# LEF file generated by Abstract Generator version 5.5.10 on Jul 30 14:47:58 2004
#
# Contains LEF for all bins.
# Options:   [x] Antenna
#            [x] Geometry
#            [x] Technology
VERSION 5.4 ;
NAMESCASESENSITIVE ON ;
BUSBITCHARS "[]" ;
DIVIDERCHAR "/" ;
UNITS
  DATABASE MICRONS 1000 ;
END UNITS

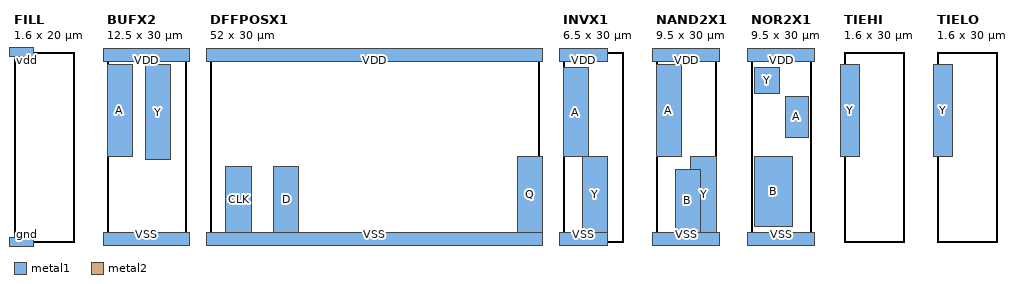
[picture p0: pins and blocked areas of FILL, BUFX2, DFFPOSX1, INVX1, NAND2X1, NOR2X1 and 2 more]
MACRO FILL
  CLASS  CORE ;
  FOREIGN FILL 0.000 0.000 ;
  ORIGIN 0.000 0.000 ;
  SIZE 1.600 BY 20.000 ;
  SYMMETRY X Y ;
  SITE core ;
  PIN gnd    DIRECTION INOUT ;
    USE GROUND ;
    SHAPE ABUTMENT ;
    PORT
      LAYER metal1 ;
        RECT -0.5 -0.5 2 0.5 ;
    END
  END gnd
  PIN vdd    DIRECTION INOUT ;
    USE POWER ;
    SHAPE ABUTMENT ;
    PORT
      LAYER metal1 ;
        RECT -0.5 19.5 2 20.5 ;
    END
  END vdd
END FILL

MACRO BUFX2
  CLASS CORE ;
  SOURCE USER ;
  ORIGIN 0 0 ;
  SIZE 12.500 BY 30.000 ;
  SYMMETRY X Y ;
  SITE unit ;
  
  PIN A    DIRECTION INPUT ;
    USE SIGNAL ;
    PORT
      LAYER metal2 ;
        RECT 0 13.5 4 28 ;
    END
    PORT
      LAYER metal1 ;
        RECT 0 13.5 4 28 ;
    END
  END A
  PIN VDD    DIRECTION INOUT ;
    USE POWER ;
    PORT
      LAYER metal1 ;
        RECT -0.5 28.5 13 30.5 ;
    END
  END VDD
  PIN VSS    DIRECTION INOUT ;
    USE GROUND ;
    PORT
      LAYER metal1 ;
        RECT -0.5 -0.5 13 1.5 ;
    END
  END VSS
  PIN Y    DIRECTION OUTPUT ;
    USE SIGNAL ;
    PORT
      LAYER metal2 ;
        RECT 6 13 10 28 ;
    END
    PORT
      LAYER metal1 ;
        RECT 6 13 10 28 ;
    END
  END Y
END BUFX2

MACRO DFFPOSX1
  CLASS CORE ;
  SOURCE USER ;
  ORIGIN 0 0 ;
  SIZE 52.000 BY 30.000 ;
  SYMMETRY X Y ;
  SITE unit ;
  
  PIN CLK    DIRECTION INPUT ;
    USE SIGNAL ;
    PORT
      LAYER metal2 ;
        RECT 2.5 1.5 6.5 12 ;
    END
    PORT
      LAYER metal1 ;
        RECT 2.5 1.5 6.5 12 ;
    END
  END CLK
  PIN D    DIRECTION INPUT ;
    USE SIGNAL ;
    PORT
      LAYER metal2 ;
        RECT 10 1.5 14 12 ;
    END
    PORT
      LAYER metal1 ;
        RECT 10 1.5 14 12 ;
    END
  END D
  PIN Q    DIRECTION OUTPUT ;
    USE SIGNAL ;
    PORT
      LAYER metal2 ;
        RECT 48.5 1.5 52.5 13.5 ;
    END
    PORT
      LAYER metal1 ;
        RECT 48.5 1.5 52.5 13.5 ;
    END
  END Q
  PIN VDD    DIRECTION INOUT ;
    USE POWER ;
    PORT
      LAYER metal1 ;
        RECT -0.5 28.5 52.5 30.5 ;
    END
  END VDD
  PIN VSS    DIRECTION INOUT ;
    USE GROUND ;
    PORT
      LAYER metal1 ;
        RECT -0.5 -0.5 52.5 1.5 ;
    END
  END VSS
END DFFPOSX1

MACRO INVX1
  CLASS CORE ;
  SOURCE USER ;
  ORIGIN 0 0 ;
  SIZE 6.500 BY 30.000 ;
  SYMMETRY X Y ;
  SITE unit ;
  
  PIN A    DIRECTION INPUT ;
    USE SIGNAL ;
    PORT
      LAYER metal2 ;
        RECT 0 13.5 4 27.5 ;
    END
    PORT
      LAYER metal1 ;
        RECT 0 13.5 4 27.5 ;
    END
  END A
  PIN VDD    DIRECTION INOUT ;
    USE POWER ;
    PORT
      LAYER metal1 ;
        RECT -0.5 28.5 7 30.5 ;
    END
  END VDD
  PIN VSS    DIRECTION INOUT ;
    USE GROUND ;
    PORT
      LAYER metal1 ;
        RECT -0.5 -0.5 7 1.5 ;
    END
  END VSS
  PIN Y    DIRECTION OUTPUT ;
    USE SIGNAL ;
    PORT
      LAYER metal2 ;
        RECT 3 1.5 7 13.5 ;
    END
    PORT
      LAYER metal1 ;
        RECT 3 1.5 7 13.5 ;
    END
  END Y
END INVX1

MACRO NAND2X1
  CLASS CORE ;
  SOURCE USER ;
  ORIGIN 0 0 ;
  SIZE 9.500 BY 30.000 ;
  SYMMETRY X Y ;
  SITE unit ;
 
  PIN A    DIRECTION INPUT ;
    USE SIGNAL ;
    PORT
      LAYER metal2 ;
        RECT 0 13.5 4 28 ;
    END
    PORT
      LAYER metal1 ;
        RECT 0 13.5 4 28 ;
    END
  END A
  PIN B    DIRECTION INPUT ;
    USE SIGNAL ;
    PORT
      LAYER metal2 ;
        RECT 3 1.5 7 11.5 ;
    END
    PORT
      LAYER metal1 ;
        RECT 3 1.5 7 11.5 ;
    END
  END B
  PIN VDD    DIRECTION INOUT ;
    USE POWER ;
    PORT
      LAYER metal1 ;
        RECT -0.5 28.5 10 30.5 ;
    END
  END VDD
  PIN VSS    DIRECTION INOUT ;
    USE GROUND ;
    PORT
      LAYER metal1 ;
        RECT -0.5 -0.5 10 1.5 ;
    END
  END VSS
  PIN Y    DIRECTION OUTPUT ;
    USE SIGNAL ;
    PORT
      LAYER metal2 ;
        RECT 5.5 1.5 9.5 13.5 ;
    END
    PORT
      LAYER metal1 ;
        RECT 5.5 1.5 9.5 13.5 ;
    END
  END Y
END NAND2X1

MACRO dcont
  CLASS CORE ;
END dcont

MACRO nsubcont
  CLASS CORE ;
END nsubcont

MACRO pcont
  CLASS CORE ;
END pcont

MACRO psubcont
  CLASS CORE ;
END psubcont


MACRO NOR2X1
  CLASS CORE ;
  SOURCE USER ;
  ORIGIN 0 0 ;
  SIZE 9.500 BY 30.000 ;
  SYMMETRY X Y ;
  SITE unit ;

  PIN A    DIRECTION INPUT ;
    USE SIGNAL ;
    PORT
      LAYER metal2 ;
        RECT 5.5 16.5 9 23 ;
    END
    PORT
      LAYER metal1 ;
        RECT 5.5 16.5 9 23 ;
    END
  END A
  PIN B    DIRECTION INPUT ;
    USE SIGNAL ;
    PORT
      LAYER metal2 ;
        RECT 0.5 2.5 6.5 13.5 ;
    END
    PORT
      LAYER metal1 ;
        RECT 0.5 2.5 6.5 13.5 ;
    END
  END B
  PIN VDD    DIRECTION INOUT ;
    USE POWER ;
    PORT
      LAYER metal1 ;
        RECT -0.5 28.5 10 30.5 ;
    END
  END VDD
  PIN VSS    DIRECTION INOUT ;
    USE GROUND ;
    PORT
      LAYER metal1 ;
        RECT -0.5 -0.5 10 1.5 ;
    END
  END VSS
  PIN Y    DIRECTION OUTPUT ;
    USE SIGNAL ;
    PORT
      LAYER metal2 ;
        RECT 0.5 23.5 4.5 27.5 ;
    END
    PORT
      LAYER metal1 ;
        RECT 0.5 23.5 4.5 27.5 ;
    END
  END Y
END NOR2X1


MACRO TIEHI
  CLASS CORE ;
  SOURCE USER ;
  ORIGIN 0 0 ;
  SIZE 1.600 BY 30.000 ;
  SYMMETRY X Y ;
  SITE unit ;
  PIN Y    DIRECTION OUTPUT ;
    USE SIGNAL ;
    PORT
      LAYER metal2 ;
        RECT -0.5 13.5 2.5 28 ;
    END
    PORT
      LAYER metal1 ;
        RECT -0.5 13.5 2.5 28 ;
    END
  END Y
END TIEHI

MACRO TIELO
  CLASS CORE ;
  SOURCE USER ;
  ORIGIN 0 0 ;
  SIZE 1.600 BY 30.000 ;
  SYMMETRY X Y ;
  SITE unit ;
  PIN Y    DIRECTION OUTPUT ;
    USE SIGNAL ;
    PORT
      LAYER metal2 ;
        RECT -0.5 13.5 2.5 28 ;
    END
    PORT
      LAYER metal1 ;
        RECT -0.5 13.5 2.5 28 ;
    END
  END Y
END TIELO

END LIBRARY
